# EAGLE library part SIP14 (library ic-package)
Single In Line

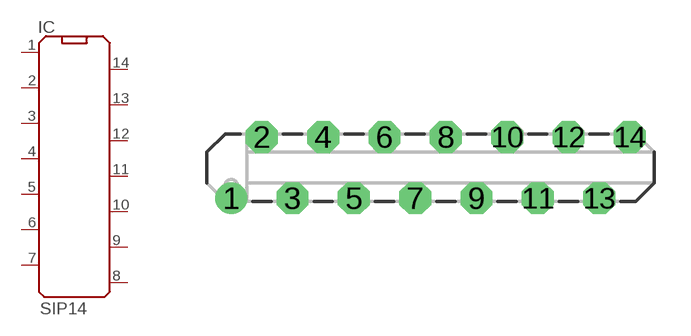
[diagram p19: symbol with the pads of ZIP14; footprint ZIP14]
Designator prefix IC

## SIP14  [ZIP14]
1  1  pas
2  2  pas
3  3  pas
4  4  pas
5  5  pas
6  6  pas
7  7  pas
8  8  pas
9  9  pas
10  10  pas
11  11  pas
12  12  pas
13  13  pas
14  14  pas

## Footprint ZIP14 (pad centres in mm)
Single In Line Socked
drill 0.813 round: 1 -8.89,-1.27
drill 0.813 octagon: 2 -7.62,1.27; 3 -6.35,-1.27; 4 -5.08,1.27; 5 -3.81,-1.27; 6 -2.54,1.27; 7 -1.27,-1.27; 8 0,1.27; 9 1.27,-1.27; 10 2.54,1.27; 11 3.81,-1.27; 12 5.08,1.27; 13 6.35,-1.27; 14 7.62,1.27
